# LEF file generated by Abstract Generator version 5.5.10 on Jul 30 14:47:58 2004
#
# Contains LEF for all bins.
# Options:   [x] Antenna
#            [x] Geometry
#            [x] Technology

VERSION 5.4 ;
NAMESCASESENSITIVE ON ;
BUSBITCHARS "[]" ;
DIVIDERCHAR "/" ;
UNITS
  DATABASE MICRONS 1000 ;
END UNITS

USEMINSPACING OBS ON ;
USEMINSPACING PIN OFF ;
CLEARANCEMEASURE EUCLIDEAN ;


MANUFACTURINGGRID 0.1 ;

MACRO PADFC
  CLASS  ENDCAP TOPLEFT ;
  FOREIGN PADFC 0.000 0.000 ;
  ORIGIN 0.000 0.000 ;
  SIZE 300.000 BY 300.000 ;
  SYMMETRY X Y R90  ;
  SITE corner ;
  OBS 
      LAYER metal4 ;
        RECT 0.600 0.600 299.400 299.400 ;
      LAYER metal3 ;
        RECT 0.600 0.600 299.400 299.400 ;
      LAYER metal2 ;
        RECT 98.000 0.000 170.400 299.400 ;
        RECT 174.800 0.000 195.800 299.400 ;
        RECT 202.200 0.000 223.200 299.400 ;
        RECT 227.600 0.000 300.000 72.400 ;
        RECT 0.600 76.800 300.000 97.800 ;
        RECT 0.600 104.000 300.000 125.200 ;
        RECT 0.600 129.600 300.000 202.000 ;
        RECT 0.600 0.600 299.400 299.400 ;
      LAYER metal1 ;
        RECT 98.000 0.000 195.800 299.400 ;
        RECT 202.200 0.000 300.000 97.800 ;
        RECT 0.600 104.000 300.000 202.000 ;
        RECT 0.600 0.600 299.400 299.400 ;
  END 
END PADFC

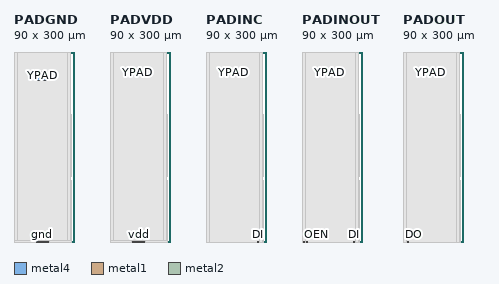
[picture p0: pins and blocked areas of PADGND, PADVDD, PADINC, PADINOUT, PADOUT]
MACRO PADGND
  CLASS  PAD ;
  FOREIGN PADGND 0.000 0.000 ;
  ORIGIN 0.000 0.000 ;
  SIZE 90.000 BY 300.000 ;
  SYMMETRY R90  ;
  SITE IO ;
  PIN YPAD
    DIRECTION OUTPUT ;
    PORT
      LAYER metal4 ;
        RECT 37.400 254.800 51.200 269.800 ;
    END
  END YPAD
  PIN gnd
    DIRECTION INOUT ;
    USE GROUND ;
    PORT
      CLASS CORE ;
      LAYER metal1 ;
        RECT 34.800 0.000 54.800 0.800 ;
    END
  END gnd
  OBS 
      LAYER metal4 ;
        RECT 0.600 0.600 89.400 253.000 ;
        RECT 0.600 271.600 89.400 299.000 ;
        RECT 0.600 0.600 35.600 299.400 ;
        RECT 53.000 0.600 89.400 299.400 ;
      LAYER metal3 ;
        RECT 0.600 0.600 89.400 299.400 ;
      LAYER metal2 ;
        RECT 0.000 0.000 90.000 72.400 ;
        RECT 0.600 76.600 89.600 97.800 ;
        RECT 0.000 76.800 90.000 97.800 ;
        RECT 0.000 104.200 90.000 125.200 ;
        RECT 0.000 129.600 90.000 202.000 ;
        RECT 0.600 0.000 89.400 299.400 ;
        RECT 6.000 0.000 84.000 300.000 ;
      LAYER metal1 ;
        RECT 0.000 0.000 34.200 97.800 ;
        RECT 55.600 0.000 90.000 97.800 ;
        RECT 0.000 104.200 90.000 202.000 ;
        RECT 0.600 1.800 89.400 299.400 ;
        RECT 6.000 1.800 84.000 300.000 ;
  END 
END PADGND

MACRO PADVDD
  CLASS  PAD ;
  FOREIGN PADVDD 0.000 0.000 ;
  ORIGIN 0.000 0.000 ;
  SIZE 90.000 BY 300.000 ;
  SYMMETRY R90  ;
  SITE IO ;
  PIN YPAD
    DIRECTION OUTPUT ;
    PORT
      LAYER metal4 ;
        RECT 42.200 266.000 44.400 268.400 ;
    END
  END YPAD
  PIN vdd
    DIRECTION INOUT ;
    USE POWER ;
    PORT
      CLASS CORE ;
      LAYER metal1 ;
        RECT 35.400 0.000 54.600 0.800 ;
    END
  END vdd
  OBS 
      LAYER metal4 ;
        RECT 0.600 0.600 89.400 264.200 ;
        RECT 0.600 270.200 89.400 299.000 ;
        RECT 0.600 0.600 40.400 299.400 ;
        RECT 46.200 0.600 89.400 299.400 ;
      LAYER metal3 ;
        RECT 0.600 0.600 89.400 299.400 ;
      LAYER metal2 ;
        RECT 0.000 0.000 34.400 72.400 ;
        RECT 35.400 0.000 54.600 300.000 ;
        RECT 55.600 0.000 90.000 72.400 ;
        RECT 0.000 76.800 90.000 97.800 ;
        RECT 0.000 104.200 90.000 125.200 ;
        RECT 0.000 129.600 90.000 202.000 ;
        RECT 0.600 1.800 89.400 299.400 ;
        RECT 6.000 1.800 84.000 300.000 ;
      LAYER metal1 ;
        RECT 0.000 0.000 34.400 97.800 ;
        RECT 55.600 0.000 90.000 97.800 ;
        RECT 0.000 104.200 90.000 202.000 ;
        RECT 0.600 1.800 89.400 299.400 ;
        RECT 6.000 1.800 84.000 300.000 ;
  END 
END PADVDD

MACRO PADINC
  CLASS  PAD ;
  FOREIGN PADINC 0.000 0.000 ;
  ORIGIN 0.000 0.000 ;
  SIZE 90.000 BY 300.000 ;
  SYMMETRY R90  ;
  SITE IO ;
  PIN YPAD
    DIRECTION OUTPUT ;
    PORT
      LAYER metal4 ;
        RECT 42.200 266.000 44.400 268.400 ;
    END
  END YPAD
  PIN DI
    DIRECTION OUTPUT ;
    PORT
      LAYER metal2 ;
        RECT 82.200 -0.400 83.000 0.400 ;
        RECT 81.600 0.000 83.400 0.400 ;
    END
  END DI
  OBS 
      LAYER metal4 ;
        RECT 0.600 0.600 89.400 264.200 ;
        RECT 0.600 270.200 89.400 299.000 ;
        RECT 0.600 0.600 40.400 299.400 ;
        RECT 46.200 0.600 89.400 299.400 ;
      LAYER metal3 ;
        RECT 0.600 0.600 80.600 299.400 ;
        RECT 84.400 0.600 89.400 299.400 ;
        RECT 0.600 1.400 89.400 299.400 ;
      LAYER metal2 ;
        RECT 0.000 0.000 34.400 72.400 ;
        RECT 35.400 0.000 54.600 300.000 ;
        RECT 55.600 0.000 78.200 300.000 ;
        RECT 79.000 0.000 80.800 300.000 ;
        RECT 0.000 0.600 80.800 72.400 ;
        RECT 84.200 0.000 90.000 72.400 ;
        RECT 0.000 76.800 90.000 97.800 ;
        RECT 0.000 104.200 90.000 125.200 ;
        RECT 0.000 129.600 90.000 202.000 ;
        RECT 0.600 1.400 89.400 299.400 ;
        RECT 6.000 1.400 84.000 300.000 ;
      LAYER metal1 ;
        RECT 0.000 0.000 90.000 97.800 ;
        RECT 0.000 104.200 90.000 202.000 ;
        RECT 0.600 0.000 89.400 299.400 ;
        RECT 6.000 0.000 84.000 300.000 ;
  END 
END PADINC

MACRO PADINOUT
  CLASS  PAD ;
  FOREIGN PADINOUT 0.000 0.000 ;
  ORIGIN 0.000 0.000 ;
  SIZE 90.000 BY 300.000 ;
  SYMMETRY R90  ;
  SITE IO ;
  PIN YPAD
    DIRECTION OUTPUT ;
    PORT
      LAYER metal4 ;
        RECT 42.200 266.000 44.400 268.400 ;
    END
  END YPAD
  PIN DO
    DIRECTION INPUT ;
    PORT
      LAYER metal2 ;
        RECT 8.200 -0.400 9.000 0.400 ;
        RECT 7.600 0.000 9.400 0.400 ;
    END
  END DO
  PIN DI
    DIRECTION OUTPUT ;
    PORT
      LAYER metal2 ;
        RECT 82.200 -0.400 83.000 0.400 ;
        RECT 81.600 0.000 83.400 0.400 ;
    END
  END DI
  PIN OEN
    DIRECTION INPUT ;
    PORT
      LAYER metal2 ;
        RECT 2.600 -0.400 3.400 0.400 ;
        RECT 2.200 0.000 4.000 0.400 ;
    END
  END OEN
  OBS 
      LAYER metal4 ;
        RECT 0.600 0.600 89.400 264.200 ;
        RECT 0.600 270.200 89.400 299.000 ;
        RECT 0.600 0.600 40.400 299.400 ;
        RECT 46.200 0.600 89.400 299.400 ;
      LAYER metal3 ;
        RECT 0.600 0.600 1.200 299.400 ;
        RECT 5.000 0.600 6.600 299.400 ;
        RECT 10.400 0.600 80.600 299.400 ;
        RECT 84.400 0.600 89.400 299.400 ;
        RECT 0.600 1.400 89.400 299.400 ;
      LAYER metal2 ;
        RECT 10.200 0.000 34.400 300.000 ;
        RECT 35.400 0.000 54.600 300.000 ;
        RECT 55.600 0.000 78.200 300.000 ;
        RECT 0.000 0.000 1.400 72.400 ;
        RECT 4.800 0.000 6.800 299.400 ;
        RECT 79.000 0.000 80.800 300.000 ;
        RECT 10.200 0.600 80.800 300.000 ;
        RECT 84.200 0.000 90.000 72.400 ;
        RECT 0.000 76.800 90.000 97.800 ;
        RECT 0.000 104.200 90.000 125.200 ;
        RECT 0.000 129.600 90.000 202.000 ;
        RECT 0.600 1.400 89.400 299.400 ;
        RECT 6.000 1.400 84.000 300.000 ;
      LAYER metal1 ;
        RECT 0.000 0.000 90.000 97.800 ;
        RECT 0.000 104.200 90.000 202.000 ;
        RECT 0.600 0.000 89.400 299.400 ;
        RECT 6.000 0.000 84.000 300.000 ;
  END 
END PADINOUT

MACRO PADNC
  CLASS  PAD ;
  FOREIGN PADNC 0.000 0.000 ;
  ORIGIN 0.000 0.000 ;
  SIZE 90.000 BY 300.000 ;
  SYMMETRY R90  ;
  SITE IO ;
  OBS 
      LAYER metal4 ;
        RECT 0.600 0.600 89.400 299.400 ;
      LAYER metal3 ;
        RECT 0.600 0.600 89.400 299.400 ;
      LAYER metal2 ;
        RECT 0.000 0.000 90.000 72.400 ;
        RECT 0.000 76.800 90.000 97.800 ;
        RECT 0.000 104.200 90.000 125.200 ;
        RECT 0.000 129.600 90.000 202.000 ;
        RECT 0.600 0.000 89.400 299.400 ;
      LAYER metal1 ;
        RECT 0.000 0.000 90.000 97.800 ;
        RECT 0.000 104.200 90.000 202.000 ;
        RECT 0.600 0.000 89.400 299.400 ;
  END 
END PADNC

MACRO PADOUT
  CLASS  PAD ;
  FOREIGN PADOUT 0.000 0.000 ;
  ORIGIN 0.000 0.000 ;
  SIZE 90.000 BY 300.000 ;
  SYMMETRY R90  ;
  SITE IO ;
  PIN YPAD
    DIRECTION OUTPUT ;
    PORT
      LAYER metal4 ;
        RECT 42.200 266.000 44.400 268.400 ;
    END
  END YPAD
  PIN DO
    DIRECTION INPUT ;
    PORT
      LAYER metal2 ;
        RECT 8.200 -0.400 9.000 0.400 ;
        RECT 7.600 0.000 9.400 0.400 ;
    END
  END DO
  OBS 
      LAYER metal4 ;
        RECT 0.600 0.600 89.400 264.200 ;
        RECT 0.600 270.200 89.400 299.000 ;
        RECT 0.600 0.600 40.400 299.400 ;
        RECT 46.200 0.600 89.400 299.400 ;
      LAYER metal3 ;
        RECT 0.600 0.600 6.600 299.400 ;
        RECT 10.400 0.600 89.400 299.400 ;
        RECT 0.600 1.400 89.400 299.400 ;
      LAYER metal2 ;
        RECT 0.000 0.000 1.400 72.400 ;
        RECT 2.200 0.000 4.000 299.400 ;
        RECT 4.800 0.000 6.800 299.400 ;
        RECT 10.200 0.000 34.400 300.000 ;
        RECT 35.400 0.000 54.600 300.000 ;
        RECT 55.600 0.000 78.200 300.000 ;
        RECT 79.000 0.000 80.800 300.000 ;
        RECT 81.600 0.000 83.400 300.000 ;
        RECT 0.000 0.600 6.800 72.400 ;
        RECT 10.200 0.600 90.000 72.400 ;
        RECT 84.200 0.000 90.000 72.400 ;
        RECT 0.000 76.800 90.000 97.800 ;
        RECT 0.000 104.200 90.000 125.200 ;
        RECT 0.000 129.600 90.000 202.000 ;
        RECT 0.600 1.400 89.400 299.400 ;
        RECT 6.000 1.400 84.000 300.000 ;
      LAYER metal1 ;
        RECT 0.000 0.000 90.000 97.800 ;
        RECT 0.000 104.200 90.000 202.000 ;
        RECT 0.600 0.000 89.400 299.400 ;
        RECT 6.000 0.000 84.000 300.000 ;
  END 
END PADOUT

END LIBRARY
